VERSION 5.7 ;
  NOWIREEXTENSIONATPIN ON ;
  DIVIDERCHAR "/" ;
  BUSBITCHARS "[]" ;
UNITS
  DATABASE MICRONS 1000 ;
END UNITS

LAYER M5V
  TYPE MASTERSLICE ;
END M5V

LAYER NWELL
  TYPE MASTERSLICE ;
END NWELL

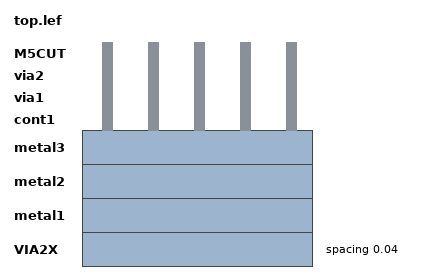
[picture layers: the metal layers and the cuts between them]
LAYER VIA2X
  TYPE ROUTING ;
  SPACING 0.040000 ;
END VIA2X

LAYER metal1
  TYPE ROUTING ;
END metal1

LAYER metal2
  TYPE ROUTING ;
END metal2

LAYER OVERLAP
  TYPE OVERLAP ;
END OVERLAP

LAYER metal3
  TYPE ROUTING ;
END metal3

LAYER cont1
  TYPE CUT ;
END cont1

LAYER via1
  TYPE CUT ;
END via1

LAYER via2
  TYPE CUT ;
END via2

LAYER M5CUT
  TYPE CUT ;
END M5CUT

MACRO top
  CLASS BLOCK ;
  FOREIGN top ;
  ORIGIN 0.000 0.000 ;
  SIZE 0.100 BY 0.100 ;
  OBS
      LAYER OBS3 ;
        RECT 0.000 0.000 0.100 0.100 ;
  END
END top
END LIBRARY

